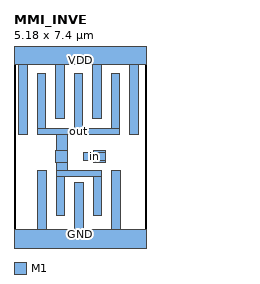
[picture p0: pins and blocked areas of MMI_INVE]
MACRO MMI_INVE
	CLASS CORE ;
	FOREIGN MMI_INVE 0 0 ;
	SIZE 5.18 BY 7.4 ;
	SYMMETRY X Y ;
	SITE CORE1 ;
	PIN out
		DIRECTION output ;
		USE SIGNAL ;
		PORT
			LAYER M1 ;
			RECT 0.9 4.41 1.24 6.555 ;
			LAYER M1 ;
			RECT 2.34 4.41 2.68 6.555 ;
			LAYER M1 ;
			RECT 3.78 4.41 4.12 6.555 ;
			LAYER M1 ;
			RECT 0.9 4.18 4.12 4.41 ;
			LAYER M1 ;
			RECT 1.64 3.555 2.075 4.18 ;
			LAYER M1 ;
			RECT 1.625 3.105 2.075 3.555 ;
			LAYER M1 ;
			RECT 1.64 2.8 2.075 3.105 ;
			LAYER M1 ;
			RECT 1.64 2.57 3.42 2.8 ;
			LAYER M1 ;
			RECT 1.64 1.04 1.98 2.57 ;
			LAYER M1 ;
			RECT 3.08 1.04 3.42 2.57 ;
		END
		AntennaDiffArea 5.9643 ;
	END out
	PIN GND
		DIRECTION inout ;
		USE GROUND ;
		PORT
			LAYER M1 ;
			RECT 0.92 0.5 1.26 2.8 ;
			LAYER M1 ;
			RECT 2.36 0.5 2.7 2.32 ;
			LAYER M1 ;
			RECT 3.8 0.5 4.14 2.8 ;
			LAYER M1 ;
			RECT 0 -0.5 5.18 0.5 ;
		END
	END GND
	PIN VDD
		DIRECTION inout ;
		USE POWER ;
		PORT
			LAYER M1 ;
			RECT 0 6.9 5.18 7.9 ;
			LAYER M1 ;
			RECT 0.18 4.18 0.52 6.9 ;
			LAYER M1 ;
			RECT 1.62 4.8 1.96 6.9 ;
			LAYER M1 ;
			RECT 3.06 4.8 3.4 6.9 ;
			LAYER M1 ;
			RECT 4.5 4.18 4.84 6.9 ;
		END
	END VDD
	PIN in
		DIRECTION input ;
		USE SIGNAL ;
		PORT
			LAYER M1 ;
			RECT 3.105 3.5 3.555 3.555 ;
			LAYER M1 ;
			RECT 2.725 3.16 3.555 3.5 ;
			LAYER M1 ;
			RECT 3.105 3.105 3.555 3.16 ;
		END
		AntennaGateArea 3.9762 ;
	END in
	OBS
	END
END MMI_INVE
